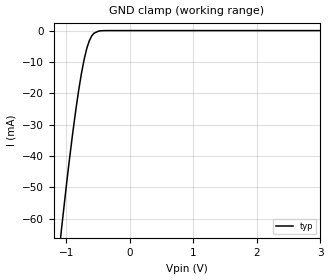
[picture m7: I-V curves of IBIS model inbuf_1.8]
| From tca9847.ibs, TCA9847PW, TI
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| inbuf_1.8
[Model]   inbuf_1.8
Model_type   Input
Vinl = .54
Vinh = 1.26
|   typ   min   max
C_comp   2pF   NA   NA
[Voltage Range]   1.8   NA   NA
[Temperature Range]   27   NA   NA
[Power Clamp Reference]   1.8   NA   NA
[GND Clamp Reference]   0   NA   NA
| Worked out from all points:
|   GND clamp passes 1 mA (typ) near -0.57 V on its own axis
[GND Clamp]
|   Voltage   I(typ)   I(min)   I(max)
-1.8V     -216.9mA   NA         NA
-1.173V   -82.26mA   NA         NA
-1.073V   -63.03mA   NA         NA
-981.8mV  -46.59mA   NA         NA
-900.6mV  -33.11mA   NA         NA
-846.9mV  -24.95mA   NA         NA
-760.5mV  -13.64mA   NA         NA
-675.5mV  -5.607mA   NA         NA
-638mV    -3.304mA   NA         NA
-562.4mV  -828.1uA   NA         NA
-369.7mV  -5.338uA   NA         NA
3.6V      0A         NA         NA
[POWER Clamp]
|   Voltage   I(typ)   I(min)   I(max)
-1.8V     0A         NA         NA
-1.7V     0A         NA         NA
-1.6V     0A         NA         NA
6V        0A         NA         NA
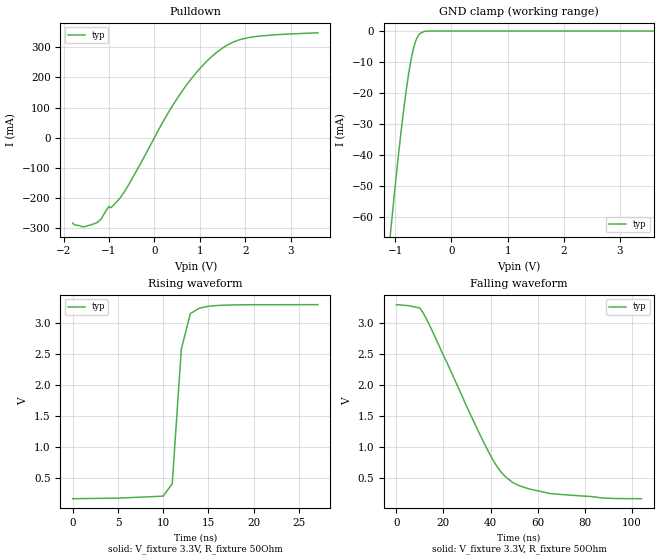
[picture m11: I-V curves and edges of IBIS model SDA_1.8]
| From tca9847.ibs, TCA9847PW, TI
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[Model]   SDA_1.8
Model_type   I/O_open_drain
Polarity   Non-Inverting
Enable   Active-Low
Vinl = 0.54
Vinh = 1.26
Vmeas = 0.9
Vref = 0
Cref = 2pF
Rref = 50
|   typ   min   max
C_comp   10pF   10pF   10pF
[Voltage Range]   3.3   NA   NA
[Temperature Range]   27   NA   NA
[Pullup Reference]   3.3   NA   NA
[Pulldown Reference]   0   NA   NA
[Power Clamp Reference]   3.3   NA   NA
[GND Clamp Reference]   0   NA   NA
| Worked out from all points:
|   slope of the pulldown table from 0 to 0.495 V, typ, clamps not added: 3.84 ohm
|   GND clamp passes 1 mA (typ) near -0.57 V on its own axis
|   falling waveform, V_fixture 3.3V, R_fixture 50Ohm: 20-80 % time 23.3ns typ, NA min, NA max; typ from 3.3 V to 0.165 V
|   rising waveform, V_fixture 3.3V, R_fixture 50Ohm: 20-80 % time 989ps typ, NA min, NA max; typ from 0.165 V to 3.3 V
[Pulldown]
|   Voltage   I(typ)   I(min)   I(max)
-1.8V     -284.2mA   NA         NA
-1.554V   -296.8mA   NA         NA
-1.264V   -282.8mA   NA         NA
-995.9mV  -227.7mA   NA         NA
-953.6mV  -233mA     NA         NA
-802.6mV  -208.8mA   NA         NA
-562.4mV  -155.3mA   NA         NA
550.8mV   141.5mA    NA         NA
941.4mV   219.6mA    NA         NA
1.395V    286.3mA    NA         NA
2.053V    331.9mA    NA         NA
3.6V      348.4mA    NA         NA
[GND Clamp]
|   Voltage   I(typ)   I(min)   I(max)
-1.8V     -216.9mA   NA         NA
-1.173V   -82.26mA   NA         NA
-1.073V   -63.03mA   NA         NA
-981.8mV  -46.59mA   NA         NA
-900.6mV  -33.11mA   NA         NA
-846.9mV  -24.95mA   NA         NA
-760.5mV  -13.64mA   NA         NA
-675.5mV  -5.607mA   NA         NA
-638mV    -3.304mA   NA         NA
-562.4mV  -828.1uA   NA         NA
-369.7mV  -5.338uA   NA         NA
3.6V      0A         NA         NA
[POWER Clamp]
|   Voltage   I(typ)   I(min)   I(max)
-1.8V     0A         NA         NA
-1.7V     0A         NA         NA
-1.6V     0A         NA         NA
6V        0A         NA         NA
[Ramp]
R_load = 50
|   typ   min   max
dV/dt_r   1.84651/1.35e-08 NA   NA
dV/dt_f   1.84651/2.8e-08   NA   NA
[Falling Waveform]
V_fixture = 3.3V
R_fixture = 50Ohm
C_fixture = 0F
|   Time   V(typ)   V(min)   V(max)
0s        3.3V       NA         NA
10ns      3.246V     NA         NA
11ns      3.191V     NA         NA
15ns      2.896V     NA         NA
39.1ns    925.7mV    NA         NA
44.2ns    608.6mV    NA         NA
49.2ns    431mV      NA         NA
55.2ns    336mV      NA         NA
65.5ns    247mV      NA         NA
104ns     165mV      NA         NA
[Rising Waveform]
V_fixture = 3.3V
R_fixture = 50Ohm
C_fixture = 0F
|   Time   V(typ)   V(min)   V(max)
0s        164.9mV    NA         NA
5ns       173.2mV    NA         NA
10ns      206.1mV    NA         NA
11ns      408.6mV    NA         NA
12ns      2.577V     NA         NA
13ns      3.156V     NA         NA
14ns      3.244V     NA         NA
16ns      3.287V     NA         NA
27.1ns    3.3V       NA         NA
